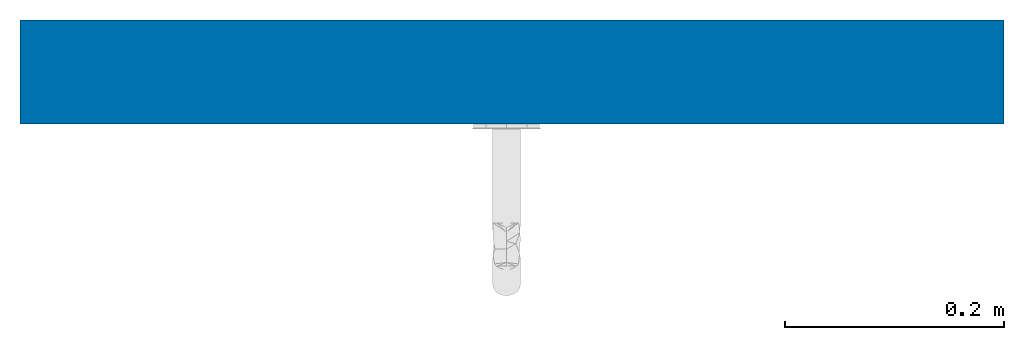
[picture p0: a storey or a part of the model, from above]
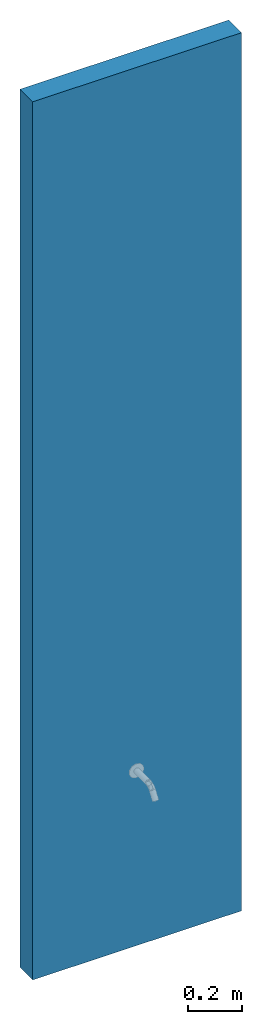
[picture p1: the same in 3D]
Properties of the parts of a building model (IFC2X3)

# File
Description: ViewDefinition [CoordinationView]
File name: Project Number
Time: 2019-04-29T17:00:26
Written by: The EXPRESS Data Manager Version 5.02.0100.07 : 28 Aug 2013
Made in: 20140606_1530(x64) - Exporter 2015.0.2014.0606 - Default UI
Comment: STEP Physical File produced by: The EXPRESS Data Manager Version 5.02.0100.07 : 28 Aug 2013 * Module: EDMstepFileFactory/EDMstandAlone * Creation date: Mon Apr 29 17:00:26 2019 * Host: SarahSams-HP * Database: C:\Users\SARAHS~1\AppData\Local\Temp\{6309B40E-8F91-4934-B002-88AEDFDFB589}\ifc * Database version: 5507 * Database creation date: Mon Apr 29 17:00:25 2019 * Schema: IFC2X3 * Model: DataRepository.ifc * Model creation date: Mon Apr 29 17:00:26 2019 * Header model: DataRepository.ifc_HeaderModel * Header model creation date: Mon Apr 29 17:00:26 2019 * EDMuser: sdai-user * EDMgroup: sdai-group * License ID and type: 5605 : Permanent license. Expiry date: * EDMstepFileFactory options: 020000

# IfcProject, Project Number
LongName: Project Name; Phase: Project Status

# IfcSite, Default
RefLatitude: 51, 30, 0, 549316; RefLongitude: 0, -7, -34, -450321; RefElevation: 0 mm
Other - Category: Project Information; Client Name: Owner; Project Address: Enter address here; Project Issue Date: Issue Date; Project Name: Project Name; Project Number: Project Number; Project Status: Project Status

# IfcBuilding
Pset_BuildingCommon - NumberOfStoreys: 1
Other - Category: Project Information; Client Name: Owner; Project Address: Enter address here; Project Issue Date: Issue Date; Project Name: Project Name; Project Number: Project Number; Project Status: Project Status

# IfcBuildingStorey, Level 0
LongName: Level 0; Elevation: 0 mm
Other - Category: Levels; Family Name: Level; Family: Level: Circle Head - Project Datum; Family and Type: Level: Circle Head - Project Datum; Type: Level: Circle Head - Project Datum; Type Id: Level: Circle Head - Project Datum
Identity Data - Type Name: Circle Head - Project Datum; Structural: no; Building Story: yes; Name: Level 0
Constraints - Elevation: 0 mm; Elevation Base: Project Base Point
Dimensions - Computation Height: 0 mm
Graphics - Color: 0; Line Pattern: Centre; Line Weight: 1; Symbol: Anno_Level_Head_Circle: Standard; Symbol at End 1 Default: yes; Symbol at End 2 Default: no

# IfcBuildingElementProxy: Transformer Brushed Stainless Steel, Duten_SoapDpnsrs_S235:Transformer Brushed Stainless Steel:265463
In: Level 0
Classification: E2020200 Furniture & Accessories (Uniformat); Material: Duten_Metal_BrushedStainlessSteel, Duten_Plastic_Black
Pset_BuildingElementProxyCommon - Reference: n/a
Pset_ManufacturerTypeInformation - ModelReference: Transformer Polished Stainless Steel; Manufacturer: Duten
Constraints - Elevation: 800 mm; Host: Basic Wall : Wall-Partn_12P-70MStd-12P; Level: Level: Level 0; Default Elevation: 1200 mm
Dimensions - Area: 0.0287535 m2; Volume: 0.000289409 m3
Other - Category: Generic Models; Family: Duten_SoapDpnsrs_S235: Transformer Brushed Stainless Steel; Family and Type: Duten_SoapDpnsrs_S235: Transformer Brushed Stainless Steel; Schedule Level: Level: Level 0; Type: Duten_SoapDpnsrs_S235: Transformer Brushed Stainless Steel; Type Id: Duten_SoapDpnsrs_S235: Transformer Brushed Stainless Steel; AccessibilityPerformance: n/a; AssetIdentifier: n/a; AssetType: Moveable; BarCode: n/a; CodePerformance: Pr_40_70_22_81: Soap dispensers; Color: Defined by Finish; Constituents: Stainless Steel Dispenser, Transformer or Battery; DurationUnit: Years; ExpectedLife: 5; Family Name: Duten_SoapDpnsrs_S235; Features: Wall-mounted electronic soap dispenser. Battery or mains powered. Accepts all types of liquid soap, except microbeads. Anti-drip valve distribution system.; Finish: Available in Brushed, Polished or Matte Black Stainless Steel; Grade: n/a; InstallationDate: 1900-12-31T23:59:59; Material: Stainless Steel; ModelNumber: S235-B_SEC; ModelReference: Transformer Polished Stainless Steel; Name: SoapDispensers_S235_Duten; ReplacementCost: 0; SerialNumber: n/a; Shape: Rectangular; Size: (H) 90mm x (L) 157mm x (W) 64mm; SustainabilityPerformance: n/a; TagNumber: n/a; WarrantyDescription: n/a; WarrantyDurationLabor: 5; WarrantyDurationParts: 5; WarrantyDurationUnit: Years; WarrantyGuarantorLabor: contact@duten.fr; WarrantyGuarantorParts: contact@duten.fr; WarrantyStartDate: 1900-12-31T23:59:59
Phasing - Phase Created: New Construction
General - Author: Diane Butterworth Ltd; ManufacturerName: Duten; ManufacturerURL: http://www.duten.fr/; NBSDescription: Soap dispensers; NBSReference: 45-35-72/358; ProductInformation: https://www.duten.fr/produits/distributeurs-savon/distributeur-savon-electronique-mural-s235; Revision: n/a; Uniclass2015Code: Pr_40_70_22_81; Uniclass2015Title: Soap dispensers; Uniclass2015Version: Pr-Products v1.10
Graphics - Include MF Pump: no
Identity Data - Assembly Code: E2020200; Assembly Description: Furniture & Accessories; Cost: 0; Description: Transformer Polished Stainless Steel; Keynote: Pr_40_70_22_81; Manufacturer: Duten; Model: S235-B_SEC; Type Comments: Transformer Polished Stainless Steel; Type Name: Transformer Brushed Stainless Steel; URL: http://www.duten.fr/
Materials and Finishes - DispenserFinish: Duten_Metal_BrushedStainlessSteel; SensorFinish: Duten_Plastic_Black

# IfcWallStandardCase: Basic Wall:Wall-Partn_12P-70MStd-12P, Basic Wall:Wall-Partn_12P-70MStd-12P:261433
In: Level 0
Type - PredefinedType: STANDARD; Material: Plaster 12.5 mm, Metal Stud Layer 70 mm, Plaster 12.5 mm
Type - Analytical Properties - Absorptance: 0.7; Heat Transfer Coefficient (U): 0.350998; Roughness: 3; Thermal mass: 26964.3; Thermal Resistance (R): 2.84902
Type - Construction - Function: Interior; Width: 95 mm; Wrapping at Inserts: Both
Type - Graphics - Coarse Scale Fill Color: 12632256; Coarse Scale Fill Pattern: Solid fill
Type - Identity Data - Type Name: Wall-Partn_12P-70MStd-12P
Type - Other - Category: Walls; Family Name: Basic Wall
Constraints - Base Constraint: Level: Level 0; Base Extension Distance: 0 mm; Base is Attached: no; Base Offset: 0 mm; Location Line: Wall Centerline; Related to Mass: no; Room Bounding: yes; Top Constraint: Level: Level 1; Top Extension Distance: 0 mm; Top is Attached: no; Top Offset: 0 mm; Unconnected Height: 4000 mm
Dimensions - Area: 3.6 m2; Length: 900 mm; Volume: 0.342 m3
Other - Family: Basic Wall: Wall-Partn_12P-70MStd-12P; Family and Type: Basic Wall: Wall-Partn_12P-70MStd-12P; Type: Basic Wall: Wall-Partn_12P-70MStd-12P; Type Id: Basic Wall: Wall-Partn_12P-70MStd-12P
Phasing - Phase Created: New Construction
Structural - Enable Analytical Model: no; Structural: no; Structural Usage: Non-bearing
Pset_WallCommon - Reference: Wall-Partn_12P-70MStd-12P; LoadBearing: no; ExtendToStructure: no; IsExternal: no; ThermalTransmittance: 0.350998 kg/K/s3
